VERSION 5.7 ;
  NAMESCASESENSITIVE ON ;
  NOWIREEXTENSIONATPIN ON ;
  DIVIDERCHAR "/" ;
  BUSBITCHARS "[]" ;
UNITS
  DATABASE MICRONS 200 ;
END UNITS

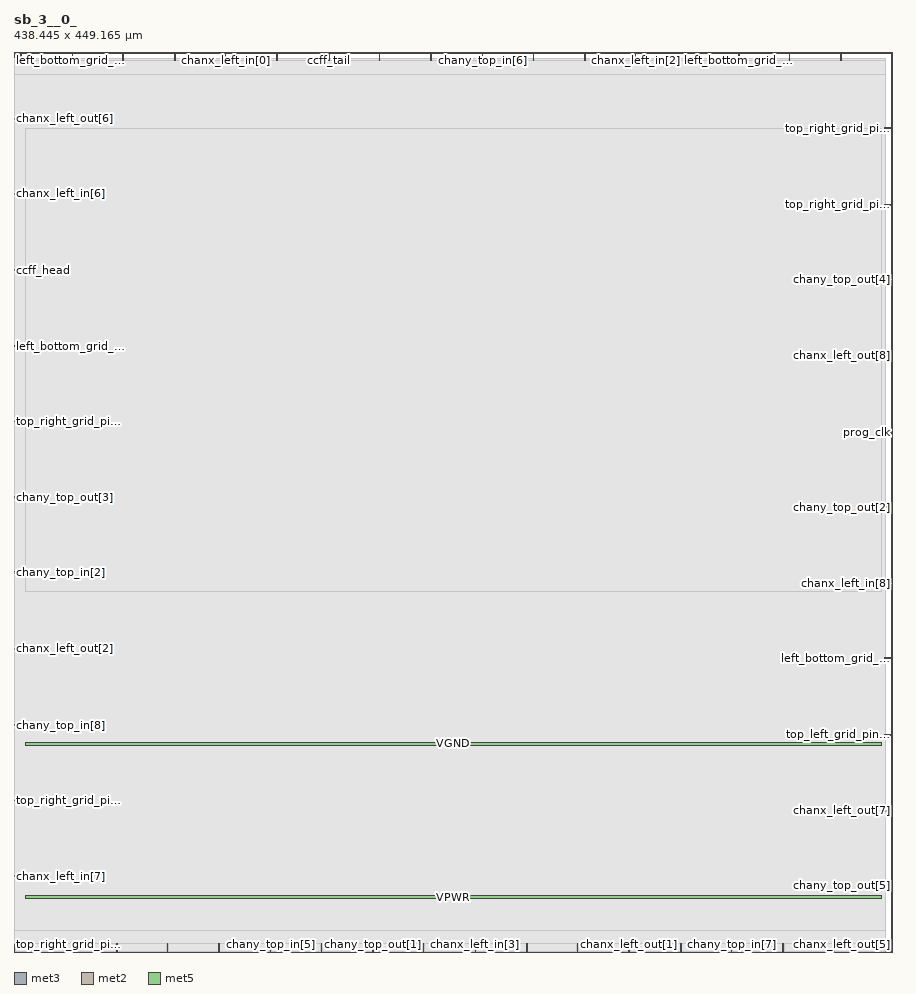
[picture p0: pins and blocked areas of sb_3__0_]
MACRO sb_3__0_
  CLASS BLOCK ;
  FOREIGN sb_3__0_ ;
  ORIGIN 0.000 0.000 ;
  SIZE 438.445 BY 449.165 ;
  PIN ccff_head
    DIRECTION INPUT ;
    PORT
      LAYER met3 ;
        RECT 0.000 340.040 4.000 340.640 ;
    END
  END ccff_head
  PIN ccff_tail
    DIRECTION OUTPUT TRISTATE ;
    PORT
      LAYER met2 ;
        RECT 156.950 445.165 157.230 449.165 ;
    END
  END ccff_tail
  PIN chanx_left_in[0]
    DIRECTION INPUT ;
    PORT
      LAYER met2 ;
        RECT 105.430 445.165 105.710 449.165 ;
    END
  END chanx_left_in[0]
  PIN chanx_left_in[1]
    DIRECTION INPUT ;
    PORT
      LAYER met2 ;
        RECT 29.070 445.165 29.350 449.165 ;
    END
  END chanx_left_in[1]
  PIN chanx_left_in[2]
    DIRECTION INPUT ;
    PORT
      LAYER met2 ;
        RECT 310.130 445.165 310.410 449.165 ;
    END
  END chanx_left_in[2]
  PIN chanx_left_in[3]
    DIRECTION INPUT ;
    PORT
      LAYER met2 ;
        RECT 230.090 0.000 230.370 4.000 ;
    END
  END chanx_left_in[3]
  PIN chanx_left_in[4]
    DIRECTION INPUT ;
    PORT
      LAYER met2 ;
        RECT 281.150 0.000 281.430 4.000 ;
    END
  END chanx_left_in[4]
  PIN chanx_left_in[5]
    DIRECTION INPUT ;
    PORT
      LAYER met2 ;
        RECT 259.070 445.165 259.350 449.165 ;
    END
  END chanx_left_in[5]
  PIN chanx_left_in[6]
    DIRECTION INPUT ;
    PORT
      LAYER met3 ;
        RECT 0.000 378.120 4.000 378.720 ;
    END
  END chanx_left_in[6]
  PIN chanx_left_in[7]
    DIRECTION INPUT ;
    PORT
      LAYER met3 ;
        RECT 0.000 37.440 4.000 38.040 ;
    END
  END chanx_left_in[7]
  PIN chanx_left_in[8]
    DIRECTION INPUT ;
    PORT
      LAYER met3 ;
        RECT 434.445 183.640 438.445 184.240 ;
    END
  END chanx_left_in[8]
  PIN chanx_left_out[0]
    DIRECTION OUTPUT TRISTATE ;
    PORT
      LAYER met2 ;
        RECT 80.130 445.165 80.410 449.165 ;
    END
  END chanx_left_out[0]
  PIN chanx_left_out[1]
    DIRECTION OUTPUT TRISTATE ;
    PORT
      LAYER met2 ;
        RECT 306.910 0.000 307.190 4.000 ;
    END
  END chanx_left_out[1]
  PIN chanx_left_out[2]
    DIRECTION OUTPUT TRISTATE ;
    PORT
      LAYER met3 ;
        RECT 0.000 151.000 4.000 151.600 ;
    END
  END chanx_left_out[2]
  PIN chanx_left_out[3]
    DIRECTION OUTPUT TRISTATE ;
    PORT
      LAYER met2 ;
        RECT 335.890 445.165 336.170 449.165 ;
    END
  END chanx_left_out[3]
  PIN chanx_left_out[4]
    DIRECTION OUTPUT TRISTATE ;
    PORT
      LAYER met2 ;
        RECT 51.150 0.000 51.430 4.000 ;
    END
  END chanx_left_out[4]
  PIN chanx_left_out[5]
    DIRECTION OUTPUT TRISTATE ;
    PORT
      LAYER met2 ;
        RECT 434.790 0.000 435.070 4.000 ;
    END
  END chanx_left_out[5]
  PIN chanx_left_out[6]
    DIRECTION OUTPUT TRISTATE ;
    PORT
      LAYER met3 ;
        RECT 0.000 415.520 4.000 416.120 ;
    END
  END chanx_left_out[6]
  PIN chanx_left_out[7]
    DIRECTION OUTPUT TRISTATE ;
    PORT
      LAYER met3 ;
        RECT 434.445 70.080 438.445 70.680 ;
    END
  END chanx_left_out[7]
  PIN chanx_left_out[8]
    DIRECTION OUTPUT TRISTATE ;
    PORT
      LAYER met3 ;
        RECT 434.445 297.200 438.445 297.800 ;
    END
  END chanx_left_out[8]
  PIN chany_top_in[0]
    DIRECTION INPUT ;
    PORT
      LAYER met2 ;
        RECT 409.030 0.000 409.310 4.000 ;
    END
  END chany_top_in[0]
  PIN chany_top_in[1]
    DIRECTION INPUT ;
    PORT
      LAYER met2 ;
        RECT 182.250 445.165 182.530 449.165 ;
    END
  END chany_top_in[1]
  PIN chany_top_in[2]
    DIRECTION INPUT ;
    PORT
      LAYER met3 ;
        RECT 0.000 189.080 4.000 189.680 ;
    END
  END chany_top_in[2]
  PIN chany_top_in[3]
    DIRECTION INPUT ;
    PORT
      LAYER met2 ;
        RECT 383.730 0.000 384.010 4.000 ;
    END
  END chany_top_in[3]
  PIN chany_top_in[4]
    DIRECTION INPUT ;
    PORT
      LAYER met2 ;
        RECT 284.830 445.165 285.110 449.165 ;
    END
  END chany_top_in[4]
  PIN chany_top_in[5]
    DIRECTION INPUT ;
    PORT
      LAYER met2 ;
        RECT 127.970 0.000 128.250 4.000 ;
    END
  END chany_top_in[5]
  PIN chany_top_in[6]
    DIRECTION INPUT ;
    PORT
      LAYER met2 ;
        RECT 233.770 445.165 234.050 449.165 ;
    END
  END chany_top_in[6]
  PIN chany_top_in[7]
    DIRECTION INPUT ;
    PORT
      LAYER met2 ;
        RECT 357.970 0.000 358.250 4.000 ;
    END
  END chany_top_in[7]
  PIN chany_top_in[8]
    DIRECTION INPUT ;
    PORT
      LAYER met3 ;
        RECT 0.000 112.920 4.000 113.520 ;
    END
  END chany_top_in[8]
  PIN chany_top_out[0]
    DIRECTION OUTPUT TRISTATE ;
    PORT
      LAYER met2 ;
        RECT 54.370 445.165 54.650 449.165 ;
    END
  END chany_top_out[0]
  PIN chany_top_out[1]
    DIRECTION OUTPUT TRISTATE ;
    PORT
      LAYER met2 ;
        RECT 179.030 0.000 179.310 4.000 ;
    END
  END chany_top_out[1]
  PIN chany_top_out[2]
    DIRECTION OUTPUT TRISTATE ;
    PORT
      LAYER met3 ;
        RECT 434.445 221.720 438.445 222.320 ;
    END
  END chany_top_out[2]
  PIN chany_top_out[3]
    DIRECTION OUTPUT TRISTATE ;
    PORT
      LAYER met3 ;
        RECT 0.000 226.480 4.000 227.080 ;
    END
  END chany_top_out[3]
  PIN chany_top_out[4]
    DIRECTION OUTPUT TRISTATE ;
    PORT
      LAYER met3 ;
        RECT 434.445 335.280 438.445 335.880 ;
    END
  END chany_top_out[4]
  PIN chany_top_out[5]
    DIRECTION OUTPUT TRISTATE ;
    PORT
      LAYER met3 ;
        RECT 434.445 32.680 438.445 33.280 ;
    END
  END chany_top_out[5]
  PIN chany_top_out[6]
    DIRECTION OUTPUT TRISTATE ;
    PORT
      LAYER met2 ;
        RECT 102.210 0.000 102.490 4.000 ;
    END
  END chany_top_out[6]
  PIN chany_top_out[7]
    DIRECTION OUTPUT TRISTATE ;
    PORT
      LAYER met2 ;
        RECT 76.450 0.000 76.730 4.000 ;
    END
  END chany_top_out[7]
  PIN chany_top_out[8]
    DIRECTION OUTPUT TRISTATE ;
    PORT
      LAYER met2 ;
        RECT 332.670 0.000 332.950 4.000 ;
    END
  END chany_top_out[8]
  PIN left_bottom_grid_pin_11_
    DIRECTION INPUT ;
    PORT
      LAYER met2 ;
        RECT 255.850 0.000 256.130 4.000 ;
    END
  END left_bottom_grid_pin_11_
  PIN left_bottom_grid_pin_13_
    DIRECTION INPUT ;
    PORT
      LAYER met2 ;
        RECT 204.330 0.000 204.610 4.000 ;
    END
  END left_bottom_grid_pin_13_
  PIN left_bottom_grid_pin_15_
    DIRECTION INPUT ;
    PORT
      LAYER met2 ;
        RECT 153.270 0.000 153.550 4.000 ;
    END
  END left_bottom_grid_pin_15_
  PIN left_bottom_grid_pin_1_
    DIRECTION INPUT ;
    PORT
      LAYER met2 ;
        RECT 3.310 445.165 3.590 449.165 ;
    END
  END left_bottom_grid_pin_1_
  PIN left_bottom_grid_pin_3_
    DIRECTION INPUT ;
    PORT
      LAYER met2 ;
        RECT 25.390 0.000 25.670 4.000 ;
    END
  END left_bottom_grid_pin_3_
  PIN left_bottom_grid_pin_5_
    DIRECTION INPUT ;
    PORT
      LAYER met2 ;
        RECT 361.650 445.165 361.930 449.165 ;
    END
  END left_bottom_grid_pin_5_
  PIN left_bottom_grid_pin_7_
    DIRECTION INPUT ;
    PORT
      LAYER met3 ;
        RECT 434.445 146.240 438.445 146.840 ;
    END
  END left_bottom_grid_pin_7_
  PIN left_bottom_grid_pin_9_
    DIRECTION INPUT ;
    PORT
      LAYER met3 ;
        RECT 0.000 301.960 4.000 302.560 ;
    END
  END left_bottom_grid_pin_9_
  PIN left_top_grid_pin_10_
    DIRECTION INPUT ;
    PORT
      LAYER met2 ;
        RECT 208.010 445.165 208.290 449.165 ;
    END
  END left_top_grid_pin_10_
  PIN pReset
    DIRECTION INPUT ;
    PORT
      LAYER met2 ;
        RECT 386.950 445.165 387.230 449.165 ;
    END
  END pReset
  PIN prog_clk
    DIRECTION INPUT ;
    PORT
      LAYER met3 ;
        RECT 434.445 259.120 438.445 259.720 ;
    END
  END prog_clk
  PIN top_left_grid_pin_13_
    DIRECTION INPUT ;
    PORT
      LAYER met3 ;
        RECT 434.445 108.160 438.445 108.760 ;
    END
  END top_left_grid_pin_13_
  PIN top_right_grid_pin_11_
    DIRECTION INPUT ;
    PORT
      LAYER met3 ;
        RECT 0.000 75.520 4.000 76.120 ;
    END
  END top_right_grid_pin_11_
  PIN top_right_grid_pin_13_
    DIRECTION INPUT ;
    PORT
      LAYER met2 ;
        RECT 412.710 445.165 412.990 449.165 ;
    END
  END top_right_grid_pin_13_
  PIN top_right_grid_pin_15_
    DIRECTION INPUT ;
    PORT
      LAYER met2 ;
        RECT 438.010 445.165 438.290 449.165 ;
    END
  END top_right_grid_pin_15_
  PIN top_right_grid_pin_1_
    DIRECTION INPUT ;
    PORT
      LAYER met3 ;
        RECT 0.000 264.560 4.000 265.160 ;
    END
  END top_right_grid_pin_1_
  PIN top_right_grid_pin_3_
    DIRECTION INPUT ;
    PORT
      LAYER met2 ;
        RECT 131.190 445.165 131.470 449.165 ;
    END
  END top_right_grid_pin_3_
  PIN top_right_grid_pin_5_
    DIRECTION INPUT ;
    PORT
      LAYER met3 ;
        RECT 434.445 410.760 438.445 411.360 ;
    END
  END top_right_grid_pin_5_
  PIN top_right_grid_pin_7_
    DIRECTION INPUT ;
    PORT
      LAYER met2 ;
        RECT 0.090 0.000 0.370 4.000 ;
    END
  END top_right_grid_pin_7_
  PIN top_right_grid_pin_9_
    DIRECTION INPUT ;
    PORT
      LAYER met3 ;
        RECT 434.445 372.680 438.445 373.280 ;
    END
  END top_right_grid_pin_9_
  PIN VPWR
    DIRECTION INPUT ;
    USE POWER ;
    PORT
      LAYER met5 ;
        RECT 5.520 26.490 432.860 28.090 ;
    END
  END VPWR
  PIN VGND
    DIRECTION INPUT ;
    USE GROUND ;
    PORT
      LAYER met5 ;
        RECT 5.520 103.080 432.860 104.680 ;
    END
  END VGND
  OBS
      LAYER li1 ;
        RECT 5.520 10.795 432.860 438.005 ;
      LAYER met1 ;
        RECT 0.530 10.640 434.630 438.160 ;
      LAYER met2 ;
        RECT 0.090 444.885 3.030 445.810 ;
        RECT 3.870 444.885 28.790 445.810 ;
        RECT 29.630 444.885 54.090 445.810 ;
        RECT 54.930 444.885 79.850 445.810 ;
        RECT 80.690 444.885 105.150 445.810 ;
        RECT 105.990 444.885 130.910 445.810 ;
        RECT 131.750 444.885 156.670 445.810 ;
        RECT 157.510 444.885 181.970 445.810 ;
        RECT 182.810 444.885 207.730 445.810 ;
        RECT 208.570 444.885 233.490 445.810 ;
        RECT 234.330 444.885 258.790 445.810 ;
        RECT 259.630 444.885 284.550 445.810 ;
        RECT 285.390 444.885 309.850 445.810 ;
        RECT 310.690 444.885 335.610 445.810 ;
        RECT 336.450 444.885 361.370 445.810 ;
        RECT 362.210 444.885 386.670 445.810 ;
        RECT 387.510 444.885 412.430 445.810 ;
        RECT 413.270 444.885 434.790 445.810 ;
        RECT 0.090 4.280 434.790 444.885 ;
        RECT 0.650 0.270 25.110 4.280 ;
        RECT 25.950 0.270 50.870 4.280 ;
        RECT 51.710 0.270 76.170 4.280 ;
        RECT 77.010 0.270 101.930 4.280 ;
        RECT 102.770 0.270 127.690 4.280 ;
        RECT 128.530 0.270 152.990 4.280 ;
        RECT 153.830 0.270 178.750 4.280 ;
        RECT 179.590 0.270 204.050 4.280 ;
        RECT 204.890 0.270 229.810 4.280 ;
        RECT 230.650 0.270 255.570 4.280 ;
        RECT 256.410 0.270 280.870 4.280 ;
        RECT 281.710 0.270 306.630 4.280 ;
        RECT 307.470 0.270 332.390 4.280 ;
        RECT 333.230 0.270 357.690 4.280 ;
        RECT 358.530 0.270 383.450 4.280 ;
        RECT 384.290 0.270 408.750 4.280 ;
        RECT 409.590 0.270 434.510 4.280 ;
      LAYER met3 ;
        RECT 0.270 416.520 434.890 438.085 ;
        RECT 4.400 415.120 434.890 416.520 ;
        RECT 0.270 411.760 434.890 415.120 ;
        RECT 0.270 410.360 434.045 411.760 ;
        RECT 0.270 379.120 434.890 410.360 ;
        RECT 4.400 377.720 434.890 379.120 ;
        RECT 0.270 373.680 434.890 377.720 ;
        RECT 0.270 372.280 434.045 373.680 ;
        RECT 0.270 341.040 434.890 372.280 ;
        RECT 4.400 339.640 434.890 341.040 ;
        RECT 0.270 336.280 434.890 339.640 ;
        RECT 0.270 334.880 434.045 336.280 ;
        RECT 0.270 302.960 434.890 334.880 ;
        RECT 4.400 301.560 434.890 302.960 ;
        RECT 0.270 298.200 434.890 301.560 ;
        RECT 0.270 296.800 434.045 298.200 ;
        RECT 0.270 265.560 434.890 296.800 ;
        RECT 4.400 264.160 434.890 265.560 ;
        RECT 0.270 260.120 434.890 264.160 ;
        RECT 0.270 258.720 434.045 260.120 ;
        RECT 0.270 227.480 434.890 258.720 ;
        RECT 4.400 226.080 434.890 227.480 ;
        RECT 0.270 222.720 434.890 226.080 ;
        RECT 0.270 221.320 434.045 222.720 ;
        RECT 0.270 190.080 434.890 221.320 ;
        RECT 4.400 188.680 434.890 190.080 ;
        RECT 0.270 184.640 434.890 188.680 ;
        RECT 0.270 183.240 434.045 184.640 ;
        RECT 0.270 152.000 434.890 183.240 ;
        RECT 4.400 150.600 434.890 152.000 ;
        RECT 0.270 147.240 434.890 150.600 ;
        RECT 0.270 145.840 434.045 147.240 ;
        RECT 0.270 113.920 434.890 145.840 ;
        RECT 4.400 112.520 434.890 113.920 ;
        RECT 0.270 109.160 434.890 112.520 ;
        RECT 0.270 107.760 434.045 109.160 ;
        RECT 0.270 76.520 434.890 107.760 ;
        RECT 4.400 75.120 434.890 76.520 ;
        RECT 0.270 71.080 434.890 75.120 ;
        RECT 0.270 69.680 434.045 71.080 ;
        RECT 0.270 38.440 434.890 69.680 ;
        RECT 4.400 37.040 434.890 38.440 ;
        RECT 0.270 33.680 434.890 37.040 ;
        RECT 0.270 32.280 434.045 33.680 ;
        RECT 0.270 10.715 434.890 32.280 ;
      LAYER met4 ;
        RECT 0.295 10.640 434.865 438.160 ;
      LAYER met5 ;
        RECT 5.520 179.670 432.860 411.040 ;
  END
END sb_3__0_
END LIBRARY

